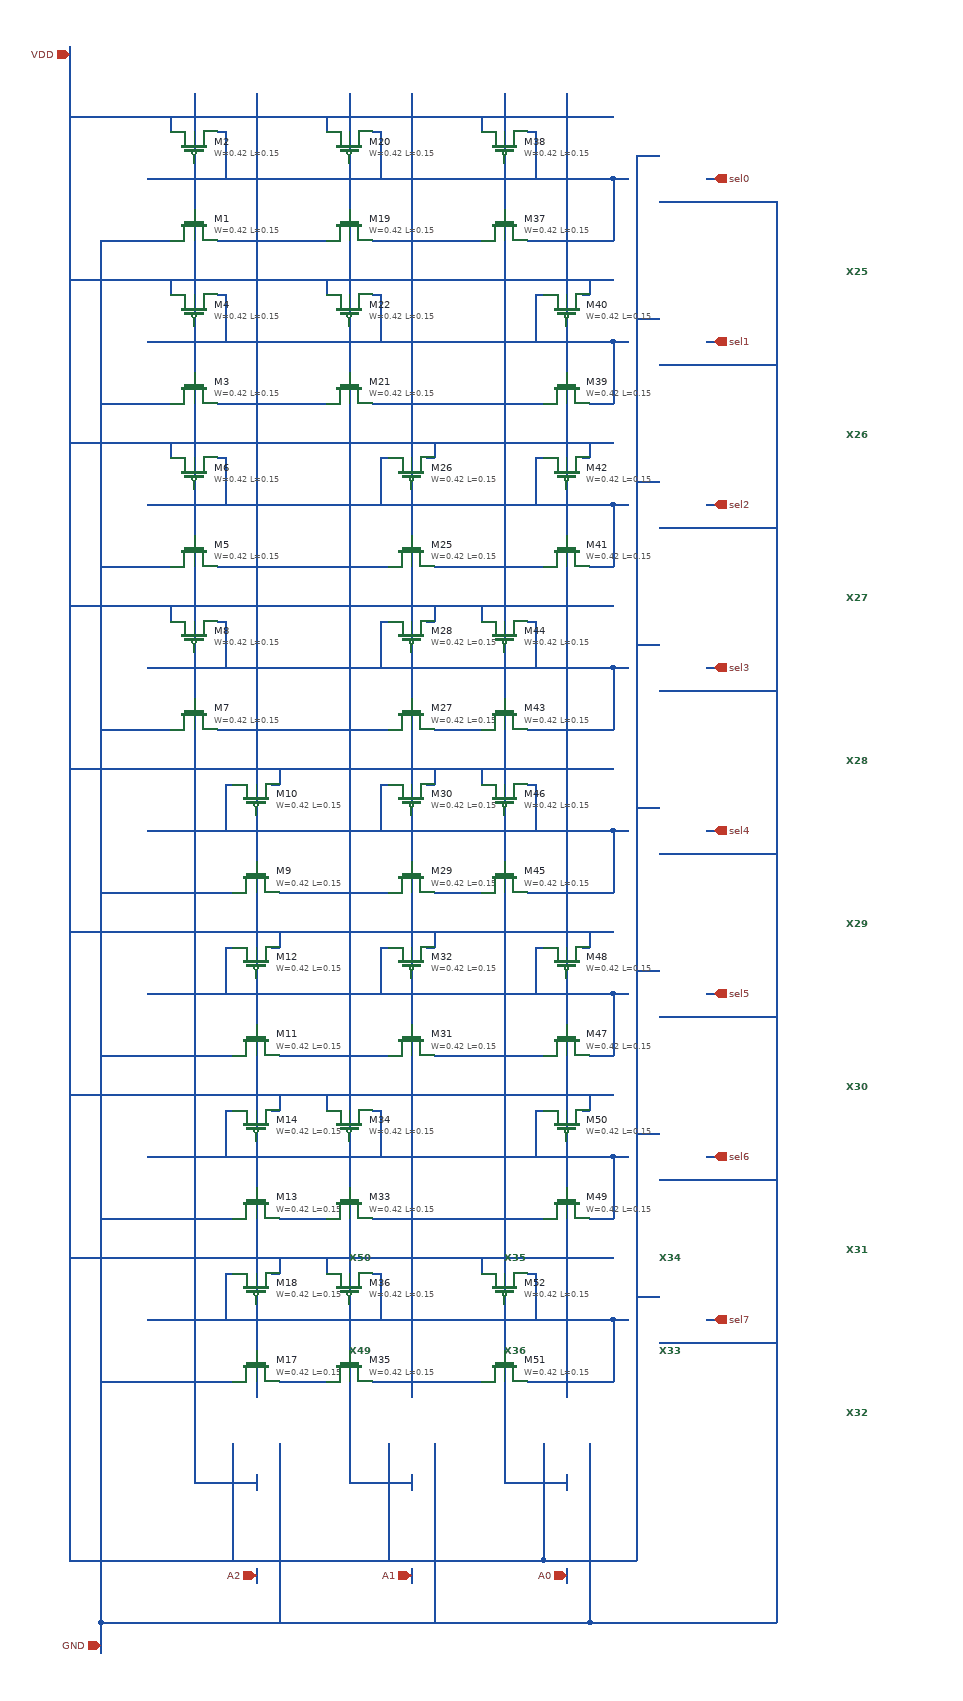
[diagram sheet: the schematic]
v {xschem version=2.9.9 file_version=1.2 }
G {}
K {}
V {}
S {}
E {}
N -1576485940 -284840100 -1576485790 -284840100 { lab=#net1}
N -1576485880 -284840160 -1576485870 -284840160 { lab=#net1}
N -1576485870 -284840160 -1576485870 -284840100 { lab=#net1}
N -1576485950 -284840100 -1576485940 -284840100 { lab=#net1}
N -1576485940 -284840180 -1576485940 -284840160 { lab=VDD}
N -1576485950 -284840020 -1576485940 -284840020 { lab=GND}
N -1576485880 -284840020 -1576485790 -284840020 { lab=#net2}
N -1576485910 -284840120 -1576485910 -284840060 { lab=#net3}
N -1576485910 -284840020 -1576485910 -284840000 { lab=#net3}
N -1576485910 -284840210 -1576485910 -284840150 { lab=#net3}
N -1576485970 -284840180 -1576485790 -284840180 { lab=VDD}
N -1576485830 -284840200 -1576485830 -284840000 { lab=#net4}
N -1576485910 -284840060 -1576485910 -284840020 { lab=#net3}
N -1576485910 -284840150 -1576485910 -284840120 { lab=#net3}
N -1576485970 -284840020 -1576485950 -284840020 { lab=GND}
N -1576485970 -284840100 -1576485950 -284840100 { lab=#net1}
N -1576485830 -284840210 -1576485830 -284840200 { lab=#net4}
N -1576485790 -284840180 -1576485770 -284840180 { lab=VDD}
N -1576485790 -284840100 -1576485770 -284840100 { lab=#net1}
N -1576485790 -284840020 -1576485770 -284840020 { lab=#net2}
N -1576485940 -284839890 -1576485790 -284839890 { lab=#net5}
N -1576485880 -284839950 -1576485870 -284839950 { lab=#net5}
N -1576485870 -284839950 -1576485870 -284839890 { lab=#net5}
N -1576485950 -284839890 -1576485940 -284839890 { lab=#net5}
N -1576485940 -284839970 -1576485940 -284839950 { lab=VDD}
N -1576485950 -284839810 -1576485940 -284839810 { lab=GND}
N -1576485880 -284839810 -1576485790 -284839810 { lab=#net6}
N -1576485910 -284839910 -1576485910 -284839850 { lab=#net3}
N -1576485910 -284839810 -1576485910 -284839790 { lab=#net3}
N -1576485910 -284840000 -1576485910 -284839940 { lab=#net3}
N -1576485970 -284839970 -1576485790 -284839970 { lab=VDD}
N -1576485830 -284839990 -1576485830 -284839790 { lab=#net4}
N -1576485910 -284839850 -1576485910 -284839810 { lab=#net3}
N -1576485910 -284839940 -1576485910 -284839910 { lab=#net3}
N -1576485970 -284839810 -1576485950 -284839810 { lab=GND}
N -1576485970 -284839890 -1576485950 -284839890 { lab=#net5}
N -1576485830 -284840000 -1576485830 -284839990 { lab=#net4}
N -1576485790 -284839970 -1576485770 -284839970 { lab=VDD}
N -1576485790 -284839890 -1576485770 -284839890 { lab=#net5}
N -1576485790 -284839810 -1576485770 -284839810 { lab=#net6}
N -1576485940 -284839680 -1576485790 -284839680 { lab=#net7}
N -1576485880 -284839740 -1576485870 -284839740 { lab=#net7}
N -1576485870 -284839740 -1576485870 -284839680 { lab=#net7}
N -1576485950 -284839680 -1576485940 -284839680 { lab=#net7}
N -1576485940 -284839760 -1576485940 -284839740 { lab=VDD}
N -1576485950 -284839600 -1576485940 -284839600 { lab=GND}
N -1576485880 -284839600 -1576485790 -284839600 { lab=#net8}
N -1576485910 -284839700 -1576485910 -284839640 { lab=#net3}
N -1576485910 -284839600 -1576485910 -284839580 { lab=#net3}
N -1576485910 -284839790 -1576485910 -284839730 { lab=#net3}
N -1576485970 -284839760 -1576485790 -284839760 { lab=VDD}
N -1576485830 -284839780 -1576485830 -284839580 { lab=#net4}
N -1576485910 -284839640 -1576485910 -284839600 { lab=#net3}
N -1576485910 -284839730 -1576485910 -284839700 { lab=#net3}
N -1576485970 -284839600 -1576485950 -284839600 { lab=GND}
N -1576485970 -284839680 -1576485950 -284839680 { lab=#net7}
N -1576485830 -284839790 -1576485830 -284839780 { lab=#net4}
N -1576485790 -284839760 -1576485770 -284839760 { lab=VDD}
N -1576485790 -284839680 -1576485770 -284839680 { lab=#net7}
N -1576485790 -284839600 -1576485770 -284839600 { lab=#net8}
N -1576485940 -284839470 -1576485790 -284839470 { lab=#net9}
N -1576485880 -284839530 -1576485870 -284839530 { lab=#net9}
N -1576485870 -284839530 -1576485870 -284839470 { lab=#net9}
N -1576485950 -284839470 -1576485940 -284839470 { lab=#net9}
N -1576485940 -284839550 -1576485940 -284839530 { lab=VDD}
N -1576485950 -284839390 -1576485940 -284839390 { lab=GND}
N -1576485880 -284839390 -1576485790 -284839390 { lab=#net10}
N -1576485910 -284839490 -1576485910 -284839430 { lab=#net3}
N -1576485910 -284839390 -1576485910 -284839370 { lab=#net3}
N -1576485910 -284839580 -1576485910 -284839520 { lab=#net3}
N -1576485970 -284839550 -1576485790 -284839550 { lab=VDD}
N -1576485830 -284839570 -1576485830 -284839370 { lab=#net4}
N -1576485910 -284839430 -1576485910 -284839390 { lab=#net3}
N -1576485910 -284839520 -1576485910 -284839490 { lab=#net3}
N -1576485970 -284839390 -1576485950 -284839390 { lab=GND}
N -1576485970 -284839470 -1576485950 -284839470 { lab=#net9}
N -1576485830 -284839580 -1576485830 -284839570 { lab=#net4}
N -1576485790 -284839550 -1576485770 -284839550 { lab=VDD}
N -1576485790 -284839470 -1576485770 -284839470 { lab=#net9}
N -1576485790 -284839390 -1576485770 -284839390 { lab=#net10}
N -1576485810 -284839320 -1576485800 -284839320 { lab=VDD}
N -1576485800 -284839340 -1576485800 -284839320 { lab=VDD}
N -1576485830 -284839280 -1576485830 -284839220 { lab=#net4}
N -1576485830 -284839180 -1576485830 -284839160 { lab=#net4}
N -1576485830 -284839370 -1576485830 -284839310 { lab=#net4}
N -1576485830 -284839220 -1576485830 -284839180 { lab=#net4}
N -1576485830 -284839310 -1576485830 -284839280 { lab=#net4}
N -1576485910 -284839370 -1576485910 -284839160 { lab=#net3}
N -1576485870 -284839320 -1576485860 -284839320 { lab=#net11}
N -1576485870 -284839320 -1576485870 -284839260 { lab=#net11}
N -1576485800 -284839180 -1576485790 -284839180 { lab=#net12}
N -1576485950 -284839180 -1576485860 -284839180 { lab=GND}
N -1576485950 -284839260 -1576485800 -284839260 { lab=#net11}
N -1576485950 -284839340 -1576485770 -284839340 { lab=VDD}
N -1576485800 -284839260 -1576485780 -284839260 { lab=#net11}
N -1576485780 -284839260 -1576485770 -284839260 { lab=#net11}
N -1576485790 -284839180 -1576485770 -284839180 { lab=#net12}
N -1576485970 -284839180 -1576485950 -284839180 { lab=GND}
N -1576485970 -284839260 -1576485950 -284839260 { lab=#net11}
N -1576485970 -284839340 -1576485950 -284839340 { lab=VDD}
N -1576485810 -284839110 -1576485800 -284839110 { lab=VDD}
N -1576485800 -284839130 -1576485800 -284839110 { lab=VDD}
N -1576485830 -284839070 -1576485830 -284839010 { lab=#net4}
N -1576485830 -284838970 -1576485830 -284838950 { lab=#net4}
N -1576485830 -284839160 -1576485830 -284839100 { lab=#net4}
N -1576485830 -284839010 -1576485830 -284838970 { lab=#net4}
N -1576485830 -284839100 -1576485830 -284839070 { lab=#net4}
N -1576485910 -284839160 -1576485910 -284838950 { lab=#net3}
N -1576485870 -284839110 -1576485860 -284839110 { lab=#net13}
N -1576485870 -284839110 -1576485870 -284839050 { lab=#net13}
N -1576485800 -284838970 -1576485790 -284838970 { lab=#net14}
N -1576485950 -284838970 -1576485860 -284838970 { lab=GND}
N -1576485950 -284839050 -1576485800 -284839050 { lab=#net13}
N -1576485950 -284839130 -1576485770 -284839130 { lab=VDD}
N -1576485800 -284839050 -1576485780 -284839050 { lab=#net13}
N -1576485780 -284839050 -1576485770 -284839050 { lab=#net13}
N -1576485790 -284838970 -1576485770 -284838970 { lab=#net14}
N -1576485970 -284838970 -1576485950 -284838970 { lab=GND}
N -1576485970 -284839050 -1576485950 -284839050 { lab=#net13}
N -1576485970 -284839130 -1576485950 -284839130 { lab=VDD}
N -1576485810 -284838900 -1576485800 -284838900 { lab=VDD}
N -1576485800 -284838920 -1576485800 -284838900 { lab=VDD}
N -1576485830 -284838860 -1576485830 -284838800 { lab=#net4}
N -1576485830 -284838760 -1576485830 -284838740 { lab=#net4}
N -1576485830 -284838950 -1576485830 -284838890 { lab=#net4}
N -1576485830 -284838800 -1576485830 -284838760 { lab=#net4}
N -1576485830 -284838890 -1576485830 -284838860 { lab=#net4}
N -1576485910 -284838950 -1576485910 -284838740 { lab=#net3}
N -1576485870 -284838900 -1576485860 -284838900 { lab=#net15}
N -1576485870 -284838900 -1576485870 -284838840 { lab=#net15}
N -1576485800 -284838760 -1576485790 -284838760 { lab=#net16}
N -1576485950 -284838760 -1576485860 -284838760 { lab=GND}
N -1576485950 -284838840 -1576485800 -284838840 { lab=#net15}
N -1576485950 -284838920 -1576485770 -284838920 { lab=VDD}
N -1576485800 -284838840 -1576485780 -284838840 { lab=#net15}
N -1576485780 -284838840 -1576485770 -284838840 { lab=#net15}
N -1576485790 -284838760 -1576485770 -284838760 { lab=#net16}
N -1576485970 -284838760 -1576485950 -284838760 { lab=GND}
N -1576485970 -284838840 -1576485950 -284838840 { lab=#net15}
N -1576485970 -284838920 -1576485950 -284838920 { lab=VDD}
N -1576485810 -284838690 -1576485800 -284838690 { lab=VDD}
N -1576485800 -284838710 -1576485800 -284838690 { lab=VDD}
N -1576485830 -284838650 -1576485830 -284838590 { lab=#net4}
N -1576485830 -284838550 -1576485830 -284838530 { lab=#net4}
N -1576485830 -284838740 -1576485830 -284838680 { lab=#net4}
N -1576485830 -284838590 -1576485830 -284838550 { lab=#net4}
N -1576485830 -284838680 -1576485830 -284838650 { lab=#net4}
N -1576485910 -284838740 -1576485910 -284838530 { lab=#net3}
N -1576485870 -284838690 -1576485860 -284838690 { lab=#net17}
N -1576485870 -284838690 -1576485870 -284838630 { lab=#net17}
N -1576485800 -284838550 -1576485790 -284838550 { lab=#net18}
N -1576485950 -284838550 -1576485860 -284838550 { lab=GND}
N -1576485950 -284838630 -1576485800 -284838630 { lab=#net17}
N -1576485950 -284838710 -1576485770 -284838710 { lab=VDD}
N -1576485800 -284838630 -1576485780 -284838630 { lab=#net17}
N -1576485780 -284838630 -1576485770 -284838630 { lab=#net17}
N -1576485790 -284838550 -1576485770 -284838550 { lab=#net18}
N -1576485970 -284838550 -1576485950 -284838550 { lab=GND}
N -1576485970 -284838630 -1576485950 -284838630 { lab=#net17}
N -1576485970 -284838710 -1576485950 -284838710 { lab=VDD}
N -1576485740 -284840100 -1576485590 -284840100 { lab=#net1}
N -1576485680 -284840160 -1576485670 -284840160 { lab=#net1}
N -1576485670 -284840160 -1576485670 -284840100 { lab=#net1}
N -1576485750 -284840100 -1576485740 -284840100 { lab=#net1}
N -1576485740 -284840180 -1576485740 -284840160 { lab=VDD}
N -1576485750 -284840020 -1576485740 -284840020 { lab=#net2}
N -1576485680 -284840020 -1576485590 -284840020 { lab=#net19}
N -1576485710 -284840120 -1576485710 -284840060 { lab=#net20}
N -1576485710 -284840020 -1576485710 -284840000 { lab=#net20}
N -1576485710 -284840210 -1576485710 -284840150 { lab=#net20}
N -1576485770 -284840180 -1576485590 -284840180 { lab=VDD}
N -1576485630 -284840200 -1576485630 -284840000 { lab=#net21}
N -1576485710 -284840060 -1576485710 -284840020 { lab=#net20}
N -1576485710 -284840150 -1576485710 -284840120 { lab=#net20}
N -1576485770 -284840020 -1576485750 -284840020 { lab=#net2}
N -1576485770 -284840100 -1576485750 -284840100 { lab=#net1}
N -1576485630 -284840210 -1576485630 -284840200 { lab=#net21}
N -1576485590 -284840180 -1576485570 -284840180 { lab=VDD}
N -1576485590 -284840100 -1576485570 -284840100 { lab=#net1}
N -1576485590 -284840020 -1576485570 -284840020 { lab=#net19}
N -1576485740 -284839890 -1576485590 -284839890 { lab=#net5}
N -1576485680 -284839950 -1576485670 -284839950 { lab=#net5}
N -1576485670 -284839950 -1576485670 -284839890 { lab=#net5}
N -1576485750 -284839890 -1576485740 -284839890 { lab=#net5}
N -1576485740 -284839970 -1576485740 -284839950 { lab=VDD}
N -1576485750 -284839810 -1576485740 -284839810 { lab=#net6}
N -1576485680 -284839810 -1576485590 -284839810 { lab=#net22}
N -1576485710 -284839910 -1576485710 -284839850 { lab=#net20}
N -1576485710 -284839810 -1576485710 -284839790 { lab=#net20}
N -1576485710 -284840000 -1576485710 -284839940 { lab=#net20}
N -1576485770 -284839970 -1576485590 -284839970 { lab=VDD}
N -1576485630 -284839990 -1576485630 -284839790 { lab=#net21}
N -1576485710 -284839850 -1576485710 -284839810 { lab=#net20}
N -1576485710 -284839940 -1576485710 -284839910 { lab=#net20}
N -1576485770 -284839810 -1576485750 -284839810 { lab=#net6}
N -1576485770 -284839890 -1576485750 -284839890 { lab=#net5}
N -1576485630 -284840000 -1576485630 -284839990 { lab=#net21}
N -1576485590 -284839970 -1576485570 -284839970 { lab=VDD}
N -1576485590 -284839890 -1576485570 -284839890 { lab=#net5}
N -1576485590 -284839810 -1576485570 -284839810 { lab=#net22}
N -1576485610 -284839740 -1576485600 -284839740 { lab=VDD}
N -1576485600 -284839760 -1576485600 -284839740 { lab=VDD}
N -1576485630 -284839700 -1576485630 -284839640 { lab=#net21}
N -1576485630 -284839600 -1576485630 -284839580 { lab=#net21}
N -1576485630 -284839790 -1576485630 -284839730 { lab=#net21}
N -1576485630 -284839640 -1576485630 -284839600 { lab=#net21}
N -1576485630 -284839730 -1576485630 -284839700 { lab=#net21}
N -1576485710 -284839790 -1576485710 -284839580 { lab=#net20}
N -1576485670 -284839740 -1576485660 -284839740 { lab=#net7}
N -1576485670 -284839740 -1576485670 -284839680 { lab=#net7}
N -1576485600 -284839600 -1576485590 -284839600 { lab=#net23}
N -1576485750 -284839600 -1576485660 -284839600 { lab=#net8}
N -1576485750 -284839680 -1576485600 -284839680 { lab=#net7}
N -1576485750 -284839760 -1576485570 -284839760 { lab=VDD}
N -1576485600 -284839680 -1576485580 -284839680 { lab=#net7}
N -1576485580 -284839680 -1576485570 -284839680 { lab=#net7}
N -1576485590 -284839600 -1576485570 -284839600 { lab=#net23}
N -1576485770 -284839600 -1576485750 -284839600 { lab=#net8}
N -1576485770 -284839680 -1576485750 -284839680 { lab=#net7}
N -1576485770 -284839760 -1576485750 -284839760 { lab=VDD}
N -1576485610 -284839530 -1576485600 -284839530 { lab=VDD}
N -1576485600 -284839550 -1576485600 -284839530 { lab=VDD}
N -1576485630 -284839490 -1576485630 -284839430 { lab=#net21}
N -1576485630 -284839390 -1576485630 -284839370 { lab=#net21}
N -1576485630 -284839580 -1576485630 -284839520 { lab=#net21}
N -1576485630 -284839430 -1576485630 -284839390 { lab=#net21}
N -1576485630 -284839520 -1576485630 -284839490 { lab=#net21}
N -1576485710 -284839580 -1576485710 -284839370 { lab=#net20}
N -1576485670 -284839530 -1576485660 -284839530 { lab=#net9}
N -1576485670 -284839530 -1576485670 -284839470 { lab=#net9}
N -1576485600 -284839390 -1576485590 -284839390 { lab=#net24}
N -1576485750 -284839390 -1576485660 -284839390 { lab=#net10}
N -1576485750 -284839470 -1576485600 -284839470 { lab=#net9}
N -1576485750 -284839550 -1576485570 -284839550 { lab=VDD}
N -1576485600 -284839470 -1576485580 -284839470 { lab=#net9}
N -1576485580 -284839470 -1576485570 -284839470 { lab=#net9}
N -1576485590 -284839390 -1576485570 -284839390 { lab=#net24}
N -1576485770 -284839390 -1576485750 -284839390 { lab=#net10}
N -1576485770 -284839470 -1576485750 -284839470 { lab=#net9}
N -1576485770 -284839550 -1576485750 -284839550 { lab=VDD}
N -1576485610 -284839320 -1576485600 -284839320 { lab=VDD}
N -1576485600 -284839340 -1576485600 -284839320 { lab=VDD}
N -1576485630 -284839280 -1576485630 -284839220 { lab=#net21}
N -1576485630 -284839180 -1576485630 -284839160 { lab=#net21}
N -1576485630 -284839370 -1576485630 -284839310 { lab=#net21}
N -1576485630 -284839220 -1576485630 -284839180 { lab=#net21}
N -1576485630 -284839310 -1576485630 -284839280 { lab=#net21}
N -1576485710 -284839370 -1576485710 -284839160 { lab=#net20}
N -1576485670 -284839320 -1576485660 -284839320 { lab=#net11}
N -1576485670 -284839320 -1576485670 -284839260 { lab=#net11}
N -1576485600 -284839180 -1576485590 -284839180 { lab=#net25}
N -1576485750 -284839180 -1576485660 -284839180 { lab=#net12}
N -1576485750 -284839260 -1576485600 -284839260 { lab=#net11}
N -1576485750 -284839340 -1576485570 -284839340 { lab=VDD}
N -1576485600 -284839260 -1576485580 -284839260 { lab=#net11}
N -1576485580 -284839260 -1576485570 -284839260 { lab=#net11}
N -1576485590 -284839180 -1576485570 -284839180 { lab=#net25}
N -1576485770 -284839180 -1576485750 -284839180 { lab=#net12}
N -1576485770 -284839260 -1576485750 -284839260 { lab=#net11}
N -1576485770 -284839340 -1576485750 -284839340 { lab=VDD}
N -1576485610 -284839110 -1576485600 -284839110 { lab=VDD}
N -1576485600 -284839130 -1576485600 -284839110 { lab=VDD}
N -1576485630 -284839070 -1576485630 -284839010 { lab=#net21}
N -1576485630 -284838970 -1576485630 -284838950 { lab=#net21}
N -1576485630 -284839160 -1576485630 -284839100 { lab=#net21}
N -1576485630 -284839010 -1576485630 -284838970 { lab=#net21}
N -1576485630 -284839100 -1576485630 -284839070 { lab=#net21}
N -1576485710 -284839160 -1576485710 -284838950 { lab=#net20}
N -1576485670 -284839110 -1576485660 -284839110 { lab=#net13}
N -1576485670 -284839110 -1576485670 -284839050 { lab=#net13}
N -1576485600 -284838970 -1576485590 -284838970 { lab=#net26}
N -1576485750 -284838970 -1576485660 -284838970 { lab=#net14}
N -1576485750 -284839050 -1576485600 -284839050 { lab=#net13}
N -1576485750 -284839130 -1576485570 -284839130 { lab=VDD}
N -1576485600 -284839050 -1576485580 -284839050 { lab=#net13}
N -1576485580 -284839050 -1576485570 -284839050 { lab=#net13}
N -1576485590 -284838970 -1576485570 -284838970 { lab=#net26}
N -1576485770 -284838970 -1576485750 -284838970 { lab=#net14}
N -1576485770 -284839050 -1576485750 -284839050 { lab=#net13}
N -1576485770 -284839130 -1576485750 -284839130 { lab=VDD}
N -1576485740 -284838840 -1576485590 -284838840 { lab=#net15}
N -1576485680 -284838900 -1576485670 -284838900 { lab=#net15}
N -1576485670 -284838900 -1576485670 -284838840 { lab=#net15}
N -1576485750 -284838840 -1576485740 -284838840 { lab=#net15}
N -1576485740 -284838920 -1576485740 -284838900 { lab=VDD}
N -1576485750 -284838760 -1576485740 -284838760 { lab=#net16}
N -1576485680 -284838760 -1576485590 -284838760 { lab=#net27}
N -1576485710 -284838860 -1576485710 -284838800 { lab=#net20}
N -1576485710 -284838760 -1576485710 -284838740 { lab=#net20}
N -1576485710 -284838950 -1576485710 -284838890 { lab=#net20}
N -1576485770 -284838920 -1576485590 -284838920 { lab=VDD}
N -1576485630 -284838940 -1576485630 -284838740 { lab=#net21}
N -1576485710 -284838800 -1576485710 -284838760 { lab=#net20}
N -1576485710 -284838890 -1576485710 -284838860 { lab=#net20}
N -1576485770 -284838760 -1576485750 -284838760 { lab=#net16}
N -1576485770 -284838840 -1576485750 -284838840 { lab=#net15}
N -1576485630 -284838950 -1576485630 -284838940 { lab=#net21}
N -1576485590 -284838920 -1576485570 -284838920 { lab=VDD}
N -1576485590 -284838840 -1576485570 -284838840 { lab=#net15}
N -1576485590 -284838760 -1576485570 -284838760 { lab=#net27}
N -1576485740 -284838630 -1576485590 -284838630 { lab=#net17}
N -1576485680 -284838690 -1576485670 -284838690 { lab=#net17}
N -1576485670 -284838690 -1576485670 -284838630 { lab=#net17}
N -1576485750 -284838630 -1576485740 -284838630 { lab=#net17}
N -1576485740 -284838710 -1576485740 -284838690 { lab=VDD}
N -1576485750 -284838550 -1576485740 -284838550 { lab=#net18}
N -1576485680 -284838550 -1576485590 -284838550 { lab=#net28}
N -1576485710 -284838650 -1576485710 -284838590 { lab=#net20}
N -1576485710 -284838550 -1576485710 -284838530 { lab=#net20}
N -1576485710 -284838740 -1576485710 -284838680 { lab=#net20}
N -1576485770 -284838710 -1576485590 -284838710 { lab=VDD}
N -1576485630 -284838730 -1576485630 -284838530 { lab=#net21}
N -1576485710 -284838590 -1576485710 -284838550 { lab=#net20}
N -1576485710 -284838680 -1576485710 -284838650 { lab=#net20}
N -1576485770 -284838550 -1576485750 -284838550 { lab=#net18}
N -1576485770 -284838630 -1576485750 -284838630 { lab=#net17}
N -1576485630 -284838740 -1576485630 -284838730 { lab=#net21}
N -1576485590 -284838710 -1576485570 -284838710 { lab=VDD}
N -1576485590 -284838630 -1576485570 -284838630 { lab=#net17}
N -1576485590 -284838550 -1576485570 -284838550 { lab=#net28}
N -1576485540 -284840100 -1576485390 -284840100 { lab=#net1}
N -1576485480 -284840160 -1576485470 -284840160 { lab=#net1}
N -1576485470 -284840160 -1576485470 -284840100 { lab=#net1}
N -1576485550 -284840100 -1576485540 -284840100 { lab=#net1}
N -1576485540 -284840180 -1576485540 -284840160 { lab=VDD}
N -1576485550 -284840020 -1576485540 -284840020 { lab=#net19}
N -1576485480 -284840020 -1576485390 -284840020 { lab=#net1}
N -1576485510 -284840120 -1576485510 -284840060 { lab=#net29}
N -1576485510 -284840020 -1576485510 -284840000 { lab=#net29}
N -1576485510 -284840210 -1576485510 -284840150 { lab=#net29}
N -1576485570 -284840180 -1576485390 -284840180 { lab=VDD}
N -1576485430 -284840200 -1576485430 -284840000 { lab=#net30}
N -1576485510 -284840060 -1576485510 -284840020 { lab=#net29}
N -1576485510 -284840150 -1576485510 -284840120 { lab=#net29}
N -1576485570 -284840020 -1576485550 -284840020 { lab=#net19}
N -1576485570 -284840100 -1576485550 -284840100 { lab=#net1}
N -1576485430 -284840210 -1576485430 -284840200 { lab=#net30}
N -1576485390 -284840180 -1576485370 -284840180 { lab=VDD}
N -1576485390 -284840100 -1576485370 -284840100 { lab=#net1}
N -1576485390 -284840020 -1576485370 -284840020 { lab=#net1}
N -1576485410 -284839950 -1576485400 -284839950 { lab=VDD}
N -1576485400 -284839970 -1576485400 -284839950 { lab=VDD}
N -1576485430 -284839910 -1576485430 -284839850 { lab=#net30}
N -1576485430 -284839810 -1576485430 -284839790 { lab=#net30}
N -1576485430 -284840000 -1576485430 -284839940 { lab=#net30}
N -1576485430 -284839850 -1576485430 -284839810 { lab=#net30}
N -1576485430 -284839940 -1576485430 -284839910 { lab=#net30}
N -1576485510 -284840000 -1576485510 -284839790 { lab=#net29}
N -1576485470 -284839950 -1576485460 -284839950 { lab=#net5}
N -1576485470 -284839950 -1576485470 -284839890 { lab=#net5}
N -1576485400 -284839810 -1576485390 -284839810 { lab=#net5}
N -1576485550 -284839810 -1576485460 -284839810 { lab=#net22}
N -1576485550 -284839890 -1576485400 -284839890 { lab=#net5}
N -1576485550 -284839970 -1576485370 -284839970 { lab=VDD}
N -1576485400 -284839890 -1576485380 -284839890 { lab=#net5}
N -1576485380 -284839890 -1576485370 -284839890 { lab=#net5}
N -1576485390 -284839810 -1576485370 -284839810 { lab=#net5}
N -1576485570 -284839810 -1576485550 -284839810 { lab=#net22}
N -1576485570 -284839890 -1576485550 -284839890 { lab=#net5}
N -1576485570 -284839970 -1576485550 -284839970 { lab=VDD}
N -1576485410 -284839740 -1576485400 -284839740 { lab=VDD}
N -1576485400 -284839760 -1576485400 -284839740 { lab=VDD}
N -1576485430 -284839700 -1576485430 -284839640 { lab=#net30}
N -1576485430 -284839600 -1576485430 -284839580 { lab=#net30}
N -1576485430 -284839790 -1576485430 -284839730 { lab=#net30}
N -1576485430 -284839640 -1576485430 -284839600 { lab=#net30}
N -1576485430 -284839730 -1576485430 -284839700 { lab=#net30}
N -1576485510 -284839790 -1576485510 -284839580 { lab=#net29}
N -1576485470 -284839740 -1576485460 -284839740 { lab=#net7}
N -1576485470 -284839740 -1576485470 -284839680 { lab=#net7}
N -1576485400 -284839600 -1576485390 -284839600 { lab=#net7}
N -1576485550 -284839600 -1576485460 -284839600 { lab=#net23}
N -1576485550 -284839680 -1576485400 -284839680 { lab=#net7}
N -1576485550 -284839760 -1576485370 -284839760 { lab=VDD}
N -1576485400 -284839680 -1576485380 -284839680 { lab=#net7}
N -1576485380 -284839680 -1576485370 -284839680 { lab=#net7}
N -1576485390 -284839600 -1576485370 -284839600 { lab=#net7}
N -1576485570 -284839600 -1576485550 -284839600 { lab=#net23}
N -1576485570 -284839680 -1576485550 -284839680 { lab=#net7}
N -1576485570 -284839760 -1576485550 -284839760 { lab=VDD}
N -1576485540 -284839470 -1576485390 -284839470 { lab=#net9}
N -1576485480 -284839530 -1576485470 -284839530 { lab=#net9}
N -1576485470 -284839530 -1576485470 -284839470 { lab=#net9}
N -1576485550 -284839470 -1576485540 -284839470 { lab=#net9}
N -1576485540 -284839550 -1576485540 -284839530 { lab=VDD}
N -1576485550 -284839390 -1576485540 -284839390 { lab=#net24}
N -1576485480 -284839390 -1576485390 -284839390 { lab=#net9}
N -1576485510 -284839490 -1576485510 -284839430 { lab=#net29}
N -1576485510 -284839390 -1576485510 -284839370 { lab=#net29}
N -1576485510 -284839580 -1576485510 -284839520 { lab=#net29}
N -1576485570 -284839550 -1576485390 -284839550 { lab=VDD}
N -1576485430 -284839570 -1576485430 -284839370 { lab=#net30}
N -1576485510 -284839430 -1576485510 -284839390 { lab=#net29}
N -1576485510 -284839520 -1576485510 -284839490 { lab=#net29}
N -1576485570 -284839390 -1576485550 -284839390 { lab=#net24}
N -1576485570 -284839470 -1576485550 -284839470 { lab=#net9}
N -1576485430 -284839580 -1576485430 -284839570 { lab=#net30}
N -1576485390 -284839550 -1576485370 -284839550 { lab=VDD}
N -1576485390 -284839470 -1576485370 -284839470 { lab=#net9}
N -1576485390 -284839390 -1576485370 -284839390 { lab=#net9}
N -1576485540 -284839260 -1576485390 -284839260 { lab=#net11}
N -1576485480 -284839320 -1576485470 -284839320 { lab=#net11}
N -1576485470 -284839320 -1576485470 -284839260 { lab=#net11}
N -1576485550 -284839260 -1576485540 -284839260 { lab=#net11}
N -1576485540 -284839340 -1576485540 -284839320 { lab=VDD}
N -1576485550 -284839180 -1576485540 -284839180 { lab=#net25}
N -1576485480 -284839180 -1576485390 -284839180 { lab=#net11}
N -1576485510 -284839280 -1576485510 -284839220 { lab=#net29}
N -1576485510 -284839180 -1576485510 -284839160 { lab=#net29}
N -1576485510 -284839370 -1576485510 -284839310 { lab=#net29}
N -1576485570 -284839340 -1576485390 -284839340 { lab=VDD}
N -1576485430 -284839360 -1576485430 -284839160 { lab=#net30}
N -1576485510 -284839220 -1576485510 -284839180 { lab=#net29}
N -1576485510 -284839310 -1576485510 -284839280 { lab=#net29}
N -1576485570 -284839180 -1576485550 -284839180 { lab=#net25}
N -1576485570 -284839260 -1576485550 -284839260 { lab=#net11}
N -1576485430 -284839370 -1576485430 -284839360 { lab=#net30}
N -1576485390 -284839340 -1576485370 -284839340 { lab=VDD}
N -1576485390 -284839260 -1576485370 -284839260 { lab=#net11}
N -1576485390 -284839180 -1576485370 -284839180 { lab=#net11}
N -1576485410 -284839110 -1576485400 -284839110 { lab=VDD}
N -1576485400 -284839130 -1576485400 -284839110 { lab=VDD}
N -1576485430 -284839070 -1576485430 -284839010 { lab=#net30}
N -1576485430 -284838970 -1576485430 -284838950 { lab=#net30}
N -1576485430 -284839160 -1576485430 -284839100 { lab=#net30}
N -1576485430 -284839010 -1576485430 -284838970 { lab=#net30}
N -1576485430 -284839100 -1576485430 -284839070 { lab=#net30}
N -1576485510 -284839160 -1576485510 -284838950 { lab=#net29}
N -1576485470 -284839110 -1576485460 -284839110 { lab=#net13}
N -1576485470 -284839110 -1576485470 -284839050 { lab=#net13}
N -1576485400 -284838970 -1576485390 -284838970 { lab=#net13}
N -1576485550 -284838970 -1576485460 -284838970 { lab=#net26}
N -1576485550 -284839050 -1576485400 -284839050 { lab=#net13}
N -1576485550 -284839130 -1576485370 -284839130 { lab=VDD}
N -1576485400 -284839050 -1576485380 -284839050 { lab=#net13}
N -1576485380 -284839050 -1576485370 -284839050 { lab=#net13}
N -1576485390 -284838970 -1576485370 -284838970 { lab=#net13}
N -1576485570 -284838970 -1576485550 -284838970 { lab=#net26}
N -1576485570 -284839050 -1576485550 -284839050 { lab=#net13}
N -1576485570 -284839130 -1576485550 -284839130 { lab=VDD}
N -1576485410 -284838900 -1576485400 -284838900 { lab=VDD}
N -1576485400 -284838920 -1576485400 -284838900 { lab=VDD}
N -1576485430 -284838860 -1576485430 -284838800 { lab=#net30}
N -1576485430 -284838760 -1576485430 -284838740 { lab=#net30}
N -1576485430 -284838950 -1576485430 -284838890 { lab=#net30}
N -1576485430 -284838800 -1576485430 -284838760 { lab=#net30}
N -1576485430 -284838890 -1576485430 -284838860 { lab=#net30}
N -1576485510 -284838950 -1576485510 -284838740 { lab=#net29}
N -1576485470 -284838900 -1576485460 -284838900 { lab=#net15}
N -1576485470 -284838900 -1576485470 -284838840 { lab=#net15}
N -1576485400 -284838760 -1576485390 -284838760 { lab=#net15}
N -1576485550 -284838760 -1576485460 -284838760 { lab=#net27}
N -1576485550 -284838840 -1576485400 -284838840 { lab=#net15}
N -1576485550 -284838920 -1576485370 -284838920 { lab=VDD}
N -1576485400 -284838840 -1576485380 -284838840 { lab=#net15}
N -1576485380 -284838840 -1576485370 -284838840 { lab=#net15}
N -1576485390 -284838760 -1576485370 -284838760 { lab=#net15}
N -1576485570 -284838760 -1576485550 -284838760 { lab=#net27}
N -1576485570 -284838840 -1576485550 -284838840 { lab=#net15}
N -1576485570 -284838920 -1576485550 -284838920 { lab=VDD}
N -1576485540 -284838630 -1576485390 -284838630 { lab=#net17}
N -1576485480 -284838690 -1576485470 -284838690 { lab=#net17}
N -1576485470 -284838690 -1576485470 -284838630 { lab=#net17}
N -1576485550 -284838630 -1576485540 -284838630 { lab=#net17}
N -1576485540 -284838710 -1576485540 -284838690 { lab=VDD}
N -1576485550 -284838550 -1576485540 -284838550 { lab=#net28}
N -1576485480 -284838550 -1576485390 -284838550 { lab=#net17}
N -1576485510 -284838650 -1576485510 -284838590 { lab=#net29}
N -1576485510 -284838550 -1576485510 -284838530 { lab=#net29}
N -1576485510 -284838740 -1576485510 -284838680 { lab=#net29}
N -1576485570 -284838710 -1576485390 -284838710 { lab=VDD}
N -1576485430 -284838730 -1576485430 -284838530 { lab=#net30}
N -1576485510 -284838590 -1576485510 -284838550 { lab=#net29}
N -1576485510 -284838680 -1576485510 -284838650 { lab=#net29}
N -1576485570 -284838550 -1576485550 -284838550 { lab=#net28}
N -1576485570 -284838630 -1576485550 -284838630 { lab=#net17}
N -1576485430 -284838740 -1576485430 -284838730 { lab=#net30}
N -1576485390 -284838710 -1576485370 -284838710 { lab=VDD}
N -1576485390 -284838630 -1576485370 -284838630 { lab=#net17}
N -1576485390 -284838550 -1576485370 -284838550 { lab=#net17}
N -1576485370 -284840100 -1576485370 -284840020 { lab=#net1}
N -1576485370 -284839890 -1576485370 -284839810 { lab=#net5}
N -1576485370 -284839680 -1576485370 -284839600 { lab=#net7}
N -1576485370 -284839470 -1576485370 -284839390 { lab=#net9}
N -1576485370 -284839260 -1576485370 -284839180 { lab=#net11}
N -1576485370 -284839050 -1576485370 -284838970 { lab=#net13}
N -1576485370 -284838840 -1576485370 -284838760 { lab=#net15}
N -1576485370 -284838630 -1576485370 -284838550 { lab=#net17}
N -1576485370 -284838630 -1576485350 -284838630 { lab=#net17}
N -1576485370 -284840100 -1576485350 -284840100 { lab=#net1}
N -1576485370 -284839890 -1576485350 -284839890 { lab=#net5}
N -1576485370 -284839680 -1576485350 -284839680 { lab=#net7}
N -1576485370 -284839470 -1576485350 -284839470 { lab=#net9}
N -1576485370 -284839260 -1576485350 -284839260 { lab=#net11}
N -1576485370 -284839050 -1576485350 -284839050 { lab=#net13}
N -1576485370 -284838840 -1576485350 -284838840 { lab=#net15}
N -1576485830 -284838430 -1576485830 -284838410 { lab=#net3}
N -1576485830 -284838310 -1576485830 -284838290 { lab=A2}
N -1576485630 -284838430 -1576485630 -284838410 { lab=#net20}
N -1576485630 -284838310 -1576485630 -284838290 { lab=A1}
N -1576485430 -284838430 -1576485430 -284838410 { lab=#net29}
N -1576485430 -284838310 -1576485430 -284838290 { lab=A0}
N -1576485800 -284838470 -1576485800 -284838240 { lab=GND}
N -1576485600 -284838470 -1576485600 -284838240 { lab=GND}
N -1576485400 -284838470 -1576485400 -284838240 { lab=GND}
N -1576485860 -284838470 -1576485860 -284838320 { lab=VDD}
N -1576485660 -284838470 -1576485660 -284838320 { lab=VDD}
N -1576485460 -284838470 -1576485460 -284838320 { lab=VDD}
N -1576485910 -284838530 -1576485910 -284838420 { lab=#net3}
N -1576485910 -284838420 -1576485830 -284838420 { lab=#net3}
N -1576485710 -284838530 -1576485710 -284838420 { lab=#net20}
N -1576485710 -284838420 -1576485630 -284838420 { lab=#net20}
N -1576485510 -284838530 -1576485510 -284838420 { lab=#net29}
N -1576485510 -284838420 -1576485430 -284838420 { lab=#net29}
N -1576486030 -284838240 -1576485400 -284838240 { lab=GND}
N -1576486030 -284838240 -1576486030 -284838200 { lab=GND}
N -1576486070 -284838320 -1576485460 -284838320 { lab=VDD}
N -1576485250 -284840100 -1576485230 -284840100 { lab=sel0}
N -1576485250 -284839890 -1576485230 -284839890 { lab=sel1}
N -1576485250 -284839680 -1576485230 -284839680 { lab=sel2}
N -1576485250 -284839470 -1576485230 -284839470 { lab=sel3}
N -1576485250 -284839260 -1576485230 -284839260 { lab=sel4}
N -1576485250 -284839050 -1576485230 -284839050 { lab=sel5}
N -1576485250 -284838840 -1576485230 -284838840 { lab=sel6}
N -1576485250 -284838630 -1576485230 -284838630 { lab=sel7}
N -1576485460 -284838320 -1576485340 -284838320 { lab=VDD}
N -1576485340 -284838680 -1576485340 -284838320 { lab=VDD}
N -1576485340 -284840130 -1576485340 -284838680 { lab=VDD}
N -1576485340 -284840130 -1576485310 -284840130 { lab=VDD}
N -1576485340 -284839920 -1576485310 -284839920 { lab=VDD}
N -1576485340 -284839710 -1576485310 -284839710 { lab=VDD}
N -1576485340 -284839500 -1576485310 -284839500 { lab=VDD}
N -1576485340 -284839290 -1576485310 -284839290 { lab=VDD}
N -1576485340 -284839080 -1576485310 -284839080 { lab=VDD}
N -1576485340 -284838870 -1576485310 -284838870 { lab=VDD}
N -1576485340 -284838660 -1576485310 -284838660 { lab=VDD}
N -1576485400 -284838240 -1576485260 -284838240 { lab=GND}
N -1576485260 -284838240 -1576485160 -284838240 { lab=GND}
N -1576485160 -284840070 -1576485160 -284838240 { lab=GND}
N -1576485310 -284840070 -1576485160 -284840070 { lab=GND}
N -1576485310 -284839860 -1576485160 -284839860 { lab=GND}
N -1576485310 -284839650 -1576485160 -284839650 { lab=GND}
N -1576485310 -284839440 -1576485160 -284839440 { lab=GND}
N -1576485310 -284839230 -1576485160 -284839230 { lab=GND}
N -1576485310 -284839020 -1576485160 -284839020 { lab=GND}
N -1576485310 -284838810 -1576485160 -284838810 { lab=GND}
N -1576485310 -284838600 -1576485160 -284838600 { lab=GND}
N -1576486070 -284840270 -1576486070 -284838340 { lab=VDD}
N -1576486070 -284840180 -1576485970 -284840180 { lab=VDD}
N -1576486070 -284839970 -1576485970 -284839970 { lab=VDD}
N -1576486070 -284839760 -1576485970 -284839760 { lab=VDD}
N -1576486070 -284839550 -1576485970 -284839550 { lab=VDD}
N -1576486070 -284839340 -1576485970 -284839340 { lab=VDD}
N -1576486070 -284839130 -1576485970 -284839130 { lab=VDD}
N -1576486070 -284838920 -1576485970 -284838920 { lab=VDD}
N -1576486070 -284838710 -1576485970 -284838710 { lab=VDD}
N -1576486070 -284838340 -1576486070 -284838320 { lab=VDD}
N -1576486030 -284840020 -1576486030 -284838240 { lab=GND}
N -1576486030 -284840020 -1576485970 -284840020 { lab=GND}
N -1576486030 -284839810 -1576485970 -284839810 { lab=GND}
N -1576486030 -284839600 -1576485970 -284839600 { lab=GND}
N -1576486030 -284839390 -1576485970 -284839390 { lab=GND}
N -1576486030 -284839180 -1576485970 -284839180 { lab=GND}
N -1576486030 -284838970 -1576485970 -284838970 { lab=GND}
N -1576486030 -284838760 -1576485970 -284838760 { lab=GND}
N -1576486030 -284838550 -1576485970 -284838550 { lab=GND}
C {sky130_fd_pr/nfet3_01v8.sym} -1576485910 -284840040 1 0 {name=M1
L=0.15
W=0.42
body=GND
nf=1
mult=1
ad="'int((nf+1)/2) * W/nf * 0.29'" 
pd="'2*int((nf+1)/2) * (W/nf + 0.29)'"
as="'int((nf+2)/2) * W/nf * 0.29'" 
ps="'2*int((nf+2)/2) * (W/nf + 0.29)'"
nrd="'0.29 / W'" nrs="'0.29 / W'"
sa=0 sb=0 sd=0
model=nfet_01v8
spiceprefix=X
}
C {sky130_fd_pr/pfet3_01v8.sym} -1576485910 -284840140 3 0 {name=M2
L=0.15
W=0.42
body=VDD
nf=1
mult=1
ad="'int((nf+1)/2) * W/nf * 0.29'" 
pd="'2*int((nf+1)/2) * (W/nf + 0.29)'"
as="'int((nf+2)/2) * W/nf * 0.29'" 
ps="'2*int((nf+2)/2) * (W/nf + 0.29)'"
nrd="'0.29 / W'" nrs="'0.29 / W'"
sa=0 sb=0 sd=0
model=pfet_01v8
spiceprefix=X
}
C {sky130_fd_pr/nfet3_01v8.sym} -1576485910 -284839830 1 0 {name=M3
L=0.15
W=0.42
body=GND
nf=1
mult=1
ad="'int((nf+1)/2) * W/nf * 0.29'" 
pd="'2*int((nf+1)/2) * (W/nf + 0.29)'"
as="'int((nf+2)/2) * W/nf * 0.29'" 
ps="'2*int((nf+2)/2) * (W/nf + 0.29)'"
nrd="'0.29 / W'" nrs="'0.29 / W'"
sa=0 sb=0 sd=0
model=nfet_01v8
spiceprefix=X
}
C {sky130_fd_pr/pfet3_01v8.sym} -1576485910 -284839930 3 0 {name=M4
L=0.15
W=0.42
body=VDD
nf=1
mult=1
ad="'int((nf+1)/2) * W/nf * 0.29'" 
pd="'2*int((nf+1)/2) * (W/nf + 0.29)'"
as="'int((nf+2)/2) * W/nf * 0.29'" 
ps="'2*int((nf+2)/2) * (W/nf + 0.29)'"
nrd="'0.29 / W'" nrs="'0.29 / W'"
sa=0 sb=0 sd=0
model=pfet_01v8
spiceprefix=X
}
C {sky130_fd_pr/nfet3_01v8.sym} -1576485910 -284839620 1 0 {name=M5
L=0.15
W=0.42
body=GND
nf=1
mult=1
ad="'int((nf+1)/2) * W/nf * 0.29'" 
pd="'2*int((nf+1)/2) * (W/nf + 0.29)'"
as="'int((nf+2)/2) * W/nf * 0.29'" 
ps="'2*int((nf+2)/2) * (W/nf + 0.29)'"
nrd="'0.29 / W'" nrs="'0.29 / W'"
sa=0 sb=0 sd=0
model=nfet_01v8
spiceprefix=X
}
C {sky130_fd_pr/pfet3_01v8.sym} -1576485910 -284839720 3 0 {name=M6
L=0.15
W=0.42
body=VDD
nf=1
mult=1
ad="'int((nf+1)/2) * W/nf * 0.29'" 
pd="'2*int((nf+1)/2) * (W/nf + 0.29)'"
as="'int((nf+2)/2) * W/nf * 0.29'" 
ps="'2*int((nf+2)/2) * (W/nf + 0.29)'"
nrd="'0.29 / W'" nrs="'0.29 / W'"
sa=0 sb=0 sd=0
model=pfet_01v8
spiceprefix=X
}
C {sky130_fd_pr/nfet3_01v8.sym} -1576485910 -284839410 1 0 {name=M7
L=0.15
W=0.42
body=GND
nf=1
mult=1
ad="'int((nf+1)/2) * W/nf * 0.29'" 
pd="'2*int((nf+1)/2) * (W/nf + 0.29)'"
as="'int((nf+2)/2) * W/nf * 0.29'" 
ps="'2*int((nf+2)/2) * (W/nf + 0.29)'"
nrd="'0.29 / W'" nrs="'0.29 / W'"
sa=0 sb=0 sd=0
model=nfet_01v8
spiceprefix=X
}
C {sky130_fd_pr/pfet3_01v8.sym} -1576485910 -284839510 3 0 {name=M8
L=0.15
W=0.42
body=VDD
nf=1
mult=1
ad="'int((nf+1)/2) * W/nf * 0.29'" 
pd="'2*int((nf+1)/2) * (W/nf + 0.29)'"
as="'int((nf+2)/2) * W/nf * 0.29'" 
ps="'2*int((nf+2)/2) * (W/nf + 0.29)'"
nrd="'0.29 / W'" nrs="'0.29 / W'"
sa=0 sb=0 sd=0
model=pfet_01v8
spiceprefix=X
}
C {sky130_fd_pr/nfet3_01v8.sym} -1576485830 -284839200 3 1 {name=M9
L=0.15
W=0.42
body=GND
nf=1
mult=1
ad="'int((nf+1)/2) * W/nf * 0.29'" 
pd="'2*int((nf+1)/2) * (W/nf + 0.29)'"
as="'int((nf+2)/2) * W/nf * 0.29'" 
ps="'2*int((nf+2)/2) * (W/nf + 0.29)'"
nrd="'0.29 / W'" nrs="'0.29 / W'"
sa=0 sb=0 sd=0
model=nfet_01v8
spiceprefix=X
}
C {sky130_fd_pr/pfet3_01v8.sym} -1576485830 -284839300 1 1 {name=M10
L=0.15
W=0.42
body=VDD
nf=1
mult=1
ad="'int((nf+1)/2) * W/nf * 0.29'" 
pd="'2*int((nf+1)/2) * (W/nf + 0.29)'"
as="'int((nf+2)/2) * W/nf * 0.29'" 
ps="'2*int((nf+2)/2) * (W/nf + 0.29)'"
nrd="'0.29 / W'" nrs="'0.29 / W'"
sa=0 sb=0 sd=0
model=pfet_01v8
spiceprefix=X
}
C {sky130_fd_pr/nfet3_01v8.sym} -1576485830 -284838990 3 1 {name=M11
L=0.15
W=0.42
body=GND
nf=1
mult=1
ad="'int((nf+1)/2) * W/nf * 0.29'" 
pd="'2*int((nf+1)/2) * (W/nf + 0.29)'"
as="'int((nf+2)/2) * W/nf * 0.29'" 
ps="'2*int((nf+2)/2) * (W/nf + 0.29)'"
nrd="'0.29 / W'" nrs="'0.29 / W'"
sa=0 sb=0 sd=0
model=nfet_01v8
spiceprefix=X
}
C {sky130_fd_pr/pfet3_01v8.sym} -1576485830 -284839090 1 1 {name=M12
L=0.15
W=0.42
body=VDD
nf=1
mult=1
ad="'int((nf+1)/2) * W/nf * 0.29'" 
pd="'2*int((nf+1)/2) * (W/nf + 0.29)'"
as="'int((nf+2)/2) * W/nf * 0.29'" 
ps="'2*int((nf+2)/2) * (W/nf + 0.29)'"
nrd="'0.29 / W'" nrs="'0.29 / W'"
sa=0 sb=0 sd=0
model=pfet_01v8
spiceprefix=X
}
C {sky130_fd_pr/nfet3_01v8.sym} -1576485830 -284838780 3 1 {name=M13
L=0.15
W=0.42
body=GND
nf=1
mult=1
ad="'int((nf+1)/2) * W/nf * 0.29'" 
pd="'2*int((nf+1)/2) * (W/nf + 0.29)'"
as="'int((nf+2)/2) * W/nf * 0.29'" 
ps="'2*int((nf+2)/2) * (W/nf + 0.29)'"
nrd="'0.29 / W'" nrs="'0.29 / W'"
sa=0 sb=0 sd=0
model=nfet_01v8
spiceprefix=X
}
C {sky130_fd_pr/pfet3_01v8.sym} -1576485830 -284838880 1 1 {name=M14
L=0.15
W=0.42
body=VDD
nf=1
mult=1
ad="'int((nf+1)/2) * W/nf * 0.29'" 
pd="'2*int((nf+1)/2) * (W/nf + 0.29)'"
as="'int((nf+2)/2) * W/nf * 0.29'" 
ps="'2*int((nf+2)/2) * (W/nf + 0.29)'"
nrd="'0.29 / W'" nrs="'0.29 / W'"
sa=0 sb=0 sd=0
model=pfet_01v8
spiceprefix=X
}
C {sky130_fd_pr/nfet3_01v8.sym} -1576485830 -284838570 3 1 {name=M17
L=0.15
W=0.42
body=GND
nf=1
mult=1
ad="'int((nf+1)/2) * W/nf * 0.29'" 
pd="'2*int((nf+1)/2) * (W/nf + 0.29)'"
as="'int((nf+2)/2) * W/nf * 0.29'" 
ps="'2*int((nf+2)/2) * (W/nf + 0.29)'"
nrd="'0.29 / W'" nrs="'0.29 / W'"
sa=0 sb=0 sd=0
model=nfet_01v8
spiceprefix=X
}
C {sky130_fd_pr/pfet3_01v8.sym} -1576485830 -284838670 1 1 {name=M18
L=0.15
W=0.42
body=VDD
nf=1
mult=1
ad="'int((nf+1)/2) * W/nf * 0.29'" 
pd="'2*int((nf+1)/2) * (W/nf + 0.29)'"
as="'int((nf+2)/2) * W/nf * 0.29'" 
ps="'2*int((nf+2)/2) * (W/nf + 0.29)'"
nrd="'0.29 / W'" nrs="'0.29 / W'"
sa=0 sb=0 sd=0
model=pfet_01v8
spiceprefix=X
}
C {sky130_fd_pr/nfet3_01v8.sym} -1576485710 -284840040 1 0 {name=M19
L=0.15
W=0.42
body=GND
nf=1
mult=1
ad="'int((nf+1)/2) * W/nf * 0.29'" 
pd="'2*int((nf+1)/2) * (W/nf + 0.29)'"
as="'int((nf+2)/2) * W/nf * 0.29'" 
ps="'2*int((nf+2)/2) * (W/nf + 0.29)'"
nrd="'0.29 / W'" nrs="'0.29 / W'"
sa=0 sb=0 sd=0
model=nfet_01v8
spiceprefix=X
}
C {sky130_fd_pr/pfet3_01v8.sym} -1576485710 -284840140 3 0 {name=M20
L=0.15
W=0.42
body=VDD
nf=1
mult=1
ad="'int((nf+1)/2) * W/nf * 0.29'" 
pd="'2*int((nf+1)/2) * (W/nf + 0.29)'"
as="'int((nf+2)/2) * W/nf * 0.29'" 
ps="'2*int((nf+2)/2) * (W/nf + 0.29)'"
nrd="'0.29 / W'" nrs="'0.29 / W'"
sa=0 sb=0 sd=0
model=pfet_01v8
spiceprefix=X
}
C {sky130_fd_pr/nfet3_01v8.sym} -1576485710 -284839830 1 0 {name=M21
L=0.15
W=0.42
body=GND
nf=1
mult=1
ad="'int((nf+1)/2) * W/nf * 0.29'" 
pd="'2*int((nf+1)/2) * (W/nf + 0.29)'"
as="'int((nf+2)/2) * W/nf * 0.29'" 
ps="'2*int((nf+2)/2) * (W/nf + 0.29)'"
nrd="'0.29 / W'" nrs="'0.29 / W'"
sa=0 sb=0 sd=0
model=nfet_01v8
spiceprefix=X
}
C {sky130_fd_pr/pfet3_01v8.sym} -1576485710 -284839930 3 0 {name=M22
L=0.15
W=0.42
body=VDD
nf=1
mult=1
ad="'int((nf+1)/2) * W/nf * 0.29'" 
pd="'2*int((nf+1)/2) * (W/nf + 0.29)'"
as="'int((nf+2)/2) * W/nf * 0.29'" 
ps="'2*int((nf+2)/2) * (W/nf + 0.29)'"
nrd="'0.29 / W'" nrs="'0.29 / W'"
sa=0 sb=0 sd=0
model=pfet_01v8
spiceprefix=X
}
C {sky130_fd_pr/nfet3_01v8.sym} -1576485630 -284839620 3 1 {name=M25
L=0.15
W=0.42
body=GND
nf=1
mult=1
ad="'int((nf+1)/2) * W/nf * 0.29'" 
pd="'2*int((nf+1)/2) * (W/nf + 0.29)'"
as="'int((nf+2)/2) * W/nf * 0.29'" 
ps="'2*int((nf+2)/2) * (W/nf + 0.29)'"
nrd="'0.29 / W'" nrs="'0.29 / W'"
sa=0 sb=0 sd=0
model=nfet_01v8
spiceprefix=X
}
C {sky130_fd_pr/pfet3_01v8.sym} -1576485630 -284839720 1 1 {name=M26
L=0.15
W=0.42
body=VDD
nf=1
mult=1
ad="'int((nf+1)/2) * W/nf * 0.29'" 
pd="'2*int((nf+1)/2) * (W/nf + 0.29)'"
as="'int((nf+2)/2) * W/nf * 0.29'" 
ps="'2*int((nf+2)/2) * (W/nf + 0.29)'"
nrd="'0.29 / W'" nrs="'0.29 / W'"
sa=0 sb=0 sd=0
model=pfet_01v8
spiceprefix=X
}
C {sky130_fd_pr/nfet3_01v8.sym} -1576485630 -284839410 3 1 {name=M27
L=0.15
W=0.42
body=GND
nf=1
mult=1
ad="'int((nf+1)/2) * W/nf * 0.29'" 
pd="'2*int((nf+1)/2) * (W/nf + 0.29)'"
as="'int((nf+2)/2) * W/nf * 0.29'" 
ps="'2*int((nf+2)/2) * (W/nf + 0.29)'"
nrd="'0.29 / W'" nrs="'0.29 / W'"
sa=0 sb=0 sd=0
model=nfet_01v8
spiceprefix=X
}
C {sky130_fd_pr/pfet3_01v8.sym} -1576485630 -284839510 1 1 {name=M28
L=0.15
W=0.42
body=VDD
nf=1
mult=1
ad="'int((nf+1)/2) * W/nf * 0.29'" 
pd="'2*int((nf+1)/2) * (W/nf + 0.29)'"
as="'int((nf+2)/2) * W/nf * 0.29'" 
ps="'2*int((nf+2)/2) * (W/nf + 0.29)'"
nrd="'0.29 / W'" nrs="'0.29 / W'"
sa=0 sb=0 sd=0
model=pfet_01v8
spiceprefix=X
}
C {sky130_fd_pr/nfet3_01v8.sym} -1576485630 -284839200 3 1 {name=M29
L=0.15
W=0.42
body=GND
nf=1
mult=1
ad="'int((nf+1)/2) * W/nf * 0.29'" 
pd="'2*int((nf+1)/2) * (W/nf + 0.29)'"
as="'int((nf+2)/2) * W/nf * 0.29'" 
ps="'2*int((nf+2)/2) * (W/nf + 0.29)'"
nrd="'0.29 / W'" nrs="'0.29 / W'"
sa=0 sb=0 sd=0
model=nfet_01v8
spiceprefix=X
}
C {sky130_fd_pr/pfet3_01v8.sym} -1576485630 -284839300 1 1 {name=M30
L=0.15
W=0.42
body=VDD
nf=1
mult=1
ad="'int((nf+1)/2) * W/nf * 0.29'" 
pd="'2*int((nf+1)/2) * (W/nf + 0.29)'"
as="'int((nf+2)/2) * W/nf * 0.29'" 
ps="'2*int((nf+2)/2) * (W/nf + 0.29)'"
nrd="'0.29 / W'" nrs="'0.29 / W'"
sa=0 sb=0 sd=0
model=pfet_01v8
spiceprefix=X
}
C {sky130_fd_pr/nfet3_01v8.sym} -1576485630 -284838990 3 1 {name=M31
L=0.15
W=0.42
body=GND
nf=1
mult=1
ad="'int((nf+1)/2) * W/nf * 0.29'" 
pd="'2*int((nf+1)/2) * (W/nf + 0.29)'"
as="'int((nf+2)/2) * W/nf * 0.29'" 
ps="'2*int((nf+2)/2) * (W/nf + 0.29)'"
nrd="'0.29 / W'" nrs="'0.29 / W'"
sa=0 sb=0 sd=0
model=nfet_01v8
spiceprefix=X
}
C {sky130_fd_pr/pfet3_01v8.sym} -1576485630 -284839090 1 1 {name=M32
L=0.15
W=0.42
body=VDD
nf=1
mult=1
ad="'int((nf+1)/2) * W/nf * 0.29'" 
pd="'2*int((nf+1)/2) * (W/nf + 0.29)'"
as="'int((nf+2)/2) * W/nf * 0.29'" 
ps="'2*int((nf+2)/2) * (W/nf + 0.29)'"
nrd="'0.29 / W'" nrs="'0.29 / W'"
sa=0 sb=0 sd=0
model=pfet_01v8
spiceprefix=X
}
C {sky130_fd_pr/nfet3_01v8.sym} -1576485710 -284838780 1 0 {name=M33
L=0.15
W=0.42
body=GND
nf=1
mult=1
ad="'int((nf+1)/2) * W/nf * 0.29'" 
pd="'2*int((nf+1)/2) * (W/nf + 0.29)'"
as="'int((nf+2)/2) * W/nf * 0.29'" 
ps="'2*int((nf+2)/2) * (W/nf + 0.29)'"
nrd="'0.29 / W'" nrs="'0.29 / W'"
sa=0 sb=0 sd=0
model=nfet_01v8
spiceprefix=X
}
C {sky130_fd_pr/pfet3_01v8.sym} -1576485710 -284838880 3 0 {name=M34
L=0.15
W=0.42
body=VDD
nf=1
mult=1
ad="'int((nf+1)/2) * W/nf * 0.29'" 
pd="'2*int((nf+1)/2) * (W/nf + 0.29)'"
as="'int((nf+2)/2) * W/nf * 0.29'" 
ps="'2*int((nf+2)/2) * (W/nf + 0.29)'"
nrd="'0.29 / W'" nrs="'0.29 / W'"
sa=0 sb=0 sd=0
model=pfet_01v8
spiceprefix=X
}
C {sky130_fd_pr/nfet3_01v8.sym} -1576485710 -284838570 1 0 {name=M35
L=0.15
W=0.42
body=GND
nf=1
mult=1
ad="'int((nf+1)/2) * W/nf * 0.29'" 
pd="'2*int((nf+1)/2) * (W/nf + 0.29)'"
as="'int((nf+2)/2) * W/nf * 0.29'" 
ps="'2*int((nf+2)/2) * (W/nf + 0.29)'"
nrd="'0.29 / W'" nrs="'0.29 / W'"
sa=0 sb=0 sd=0
model=nfet_01v8
spiceprefix=X
}
C {sky130_fd_pr/pfet3_01v8.sym} -1576485710 -284838670 3 0 {name=M36
L=0.15
W=0.42
body=VDD
nf=1
mult=1
ad="'int((nf+1)/2) * W/nf * 0.29'" 
pd="'2*int((nf+1)/2) * (W/nf + 0.29)'"
as="'int((nf+2)/2) * W/nf * 0.29'" 
ps="'2*int((nf+2)/2) * (W/nf + 0.29)'"
nrd="'0.29 / W'" nrs="'0.29 / W'"
sa=0 sb=0 sd=0
model=pfet_01v8
spiceprefix=X
}
C {sky130_fd_pr/nfet3_01v8.sym} -1576485510 -284840040 1 0 {name=M37
L=0.15
W=0.42
body=GND
nf=1
mult=1
ad="'int((nf+1)/2) * W/nf * 0.29'" 
pd="'2*int((nf+1)/2) * (W/nf + 0.29)'"
as="'int((nf+2)/2) * W/nf * 0.29'" 
ps="'2*int((nf+2)/2) * (W/nf + 0.29)'"
nrd="'0.29 / W'" nrs="'0.29 / W'"
sa=0 sb=0 sd=0
model=nfet_01v8
spiceprefix=X
}
C {sky130_fd_pr/pfet3_01v8.sym} -1576485510 -284840140 3 0 {name=M38
L=0.15
W=0.42
body=VDD
nf=1
mult=1
ad="'int((nf+1)/2) * W/nf * 0.29'" 
pd="'2*int((nf+1)/2) * (W/nf + 0.29)'"
as="'int((nf+2)/2) * W/nf * 0.29'" 
ps="'2*int((nf+2)/2) * (W/nf + 0.29)'"
nrd="'0.29 / W'" nrs="'0.29 / W'"
sa=0 sb=0 sd=0
model=pfet_01v8
spiceprefix=X
}
C {sky130_fd_pr/nfet3_01v8.sym} -1576485430 -284839830 3 1 {name=M39
L=0.15
W=0.42
body=GND
nf=1
mult=1
ad="'int((nf+1)/2) * W/nf * 0.29'" 
pd="'2*int((nf+1)/2) * (W/nf + 0.29)'"
as="'int((nf+2)/2) * W/nf * 0.29'" 
ps="'2*int((nf+2)/2) * (W/nf + 0.29)'"
nrd="'0.29 / W'" nrs="'0.29 / W'"
sa=0 sb=0 sd=0
model=nfet_01v8
spiceprefix=X
}
C {sky130_fd_pr/pfet3_01v8.sym} -1576485430 -284839930 1 1 {name=M40
L=0.15
W=0.42
body=VDD
nf=1
mult=1
ad="'int((nf+1)/2) * W/nf * 0.29'" 
pd="'2*int((nf+1)/2) * (W/nf + 0.29)'"
as="'int((nf+2)/2) * W/nf * 0.29'" 
ps="'2*int((nf+2)/2) * (W/nf + 0.29)'"
nrd="'0.29 / W'" nrs="'0.29 / W'"
sa=0 sb=0 sd=0
model=pfet_01v8
spiceprefix=X
}
C {sky130_fd_pr/nfet3_01v8.sym} -1576485430 -284839620 3 1 {name=M41
L=0.15
W=0.42
body=GND
nf=1
mult=1
ad="'int((nf+1)/2) * W/nf * 0.29'" 
pd="'2*int((nf+1)/2) * (W/nf + 0.29)'"
as="'int((nf+2)/2) * W/nf * 0.29'" 
ps="'2*int((nf+2)/2) * (W/nf + 0.29)'"
nrd="'0.29 / W'" nrs="'0.29 / W'"
sa=0 sb=0 sd=0
model=nfet_01v8
spiceprefix=X
}
C {sky130_fd_pr/pfet3_01v8.sym} -1576485430 -284839720 1 1 {name=M42
L=0.15
W=0.42
body=VDD
nf=1
mult=1
ad="'int((nf+1)/2) * W/nf * 0.29'" 
pd="'2*int((nf+1)/2) * (W/nf + 0.29)'"
as="'int((nf+2)/2) * W/nf * 0.29'" 
ps="'2*int((nf+2)/2) * (W/nf + 0.29)'"
nrd="'0.29 / W'" nrs="'0.29 / W'"
sa=0 sb=0 sd=0
model=pfet_01v8
spiceprefix=X
}
C {sky130_fd_pr/nfet3_01v8.sym} -1576485510 -284839410 1 0 {name=M43
L=0.15
W=0.42
body=GND
nf=1
mult=1
ad="'int((nf+1)/2) * W/nf * 0.29'" 
pd="'2*int((nf+1)/2) * (W/nf + 0.29)'"
as="'int((nf+2)/2) * W/nf * 0.29'" 
ps="'2*int((nf+2)/2) * (W/nf + 0.29)'"
nrd="'0.29 / W'" nrs="'0.29 / W'"
sa=0 sb=0 sd=0
model=nfet_01v8
spiceprefix=X
}
C {sky130_fd_pr/pfet3_01v8.sym} -1576485510 -284839510 3 0 {name=M44
L=0.15
W=0.42
body=VDD
nf=1
mult=1
ad="'int((nf+1)/2) * W/nf * 0.29'" 
pd="'2*int((nf+1)/2) * (W/nf + 0.29)'"
as="'int((nf+2)/2) * W/nf * 0.29'" 
ps="'2*int((nf+2)/2) * (W/nf + 0.29)'"
nrd="'0.29 / W'" nrs="'0.29 / W'"
sa=0 sb=0 sd=0
model=pfet_01v8
spiceprefix=X
}
C {sky130_fd_pr/nfet3_01v8.sym} -1576485510 -284839200 1 0 {name=M45
L=0.15
W=0.42
body=GND
nf=1
mult=1
ad="'int((nf+1)/2) * W/nf * 0.29'" 
pd="'2*int((nf+1)/2) * (W/nf + 0.29)'"
as="'int((nf+2)/2) * W/nf * 0.29'" 
ps="'2*int((nf+2)/2) * (W/nf + 0.29)'"
nrd="'0.29 / W'" nrs="'0.29 / W'"
sa=0 sb=0 sd=0
model=nfet_01v8
spiceprefix=X
}
C {sky130_fd_pr/pfet3_01v8.sym} -1576485510 -284839300 3 0 {name=M46
L=0.15
W=0.42
body=VDD
nf=1
mult=1
ad="'int((nf+1)/2) * W/nf * 0.29'" 
pd="'2*int((nf+1)/2) * (W/nf + 0.29)'"
as="'int((nf+2)/2) * W/nf * 0.29'" 
ps="'2*int((nf+2)/2) * (W/nf + 0.29)'"
nrd="'0.29 / W'" nrs="'0.29 / W'"
sa=0 sb=0 sd=0
model=pfet_01v8
spiceprefix=X
}
C {sky130_fd_pr/nfet3_01v8.sym} -1576485430 -284838990 3 1 {name=M47
L=0.15
W=0.42
body=GND
nf=1
mult=1
ad="'int((nf+1)/2) * W/nf * 0.29'" 
pd="'2*int((nf+1)/2) * (W/nf + 0.29)'"
as="'int((nf+2)/2) * W/nf * 0.29'" 
ps="'2*int((nf+2)/2) * (W/nf + 0.29)'"
nrd="'0.29 / W'" nrs="'0.29 / W'"
sa=0 sb=0 sd=0
model=nfet_01v8
spiceprefix=X
}
C {sky130_fd_pr/pfet3_01v8.sym} -1576485430 -284839090 1 1 {name=M48
L=0.15
W=0.42
body=VDD
nf=1
mult=1
ad="'int((nf+1)/2) * W/nf * 0.29'" 
pd="'2*int((nf+1)/2) * (W/nf + 0.29)'"
as="'int((nf+2)/2) * W/nf * 0.29'" 
ps="'2*int((nf+2)/2) * (W/nf + 0.29)'"
nrd="'0.29 / W'" nrs="'0.29 / W'"
sa=0 sb=0 sd=0
model=pfet_01v8
spiceprefix=X
}
C {sky130_fd_pr/nfet3_01v8.sym} -1576485430 -284838780 3 1 {name=M49
L=0.15
W=0.42
body=GND
nf=1
mult=1
ad="'int((nf+1)/2) * W/nf * 0.29'" 
pd="'2*int((nf+1)/2) * (W/nf + 0.29)'"
as="'int((nf+2)/2) * W/nf * 0.29'" 
ps="'2*int((nf+2)/2) * (W/nf + 0.29)'"
nrd="'0.29 / W'" nrs="'0.29 / W'"
sa=0 sb=0 sd=0
model=nfet_01v8
spiceprefix=X
}
C {sky130_fd_pr/pfet3_01v8.sym} -1576485430 -284838880 1 1 {name=M50
L=0.15
W=0.42
body=VDD
nf=1
mult=1
ad="'int((nf+1)/2) * W/nf * 0.29'" 
pd="'2*int((nf+1)/2) * (W/nf + 0.29)'"
as="'int((nf+2)/2) * W/nf * 0.29'" 
ps="'2*int((nf+2)/2) * (W/nf + 0.29)'"
nrd="'0.29 / W'" nrs="'0.29 / W'"
sa=0 sb=0 sd=0
model=pfet_01v8
spiceprefix=X
}
C {sky130_fd_pr/nfet3_01v8.sym} -1576485510 -284838570 1 0 {name=M51
L=0.15
W=0.42
body=GND
nf=1
mult=1
ad="'int((nf+1)/2) * W/nf * 0.29'" 
pd="'2*int((nf+1)/2) * (W/nf + 0.29)'"
as="'int((nf+2)/2) * W/nf * 0.29'" 
ps="'2*int((nf+2)/2) * (W/nf + 0.29)'"
nrd="'0.29 / W'" nrs="'0.29 / W'"
sa=0 sb=0 sd=0
model=nfet_01v8
spiceprefix=X
}
C {sky130_fd_pr/pfet3_01v8.sym} -1576485510 -284838670 3 0 {name=M52
L=0.15
W=0.42
body=VDD
nf=1
mult=1
ad="'int((nf+1)/2) * W/nf * 0.29'" 
pd="'2*int((nf+1)/2) * (W/nf + 0.29)'"
as="'int((nf+2)/2) * W/nf * 0.29'" 
ps="'2*int((nf+2)/2) * (W/nf + 0.29)'"
nrd="'0.29 / W'" nrs="'0.29 / W'"
sa=0 sb=0 sd=0
model=pfet_01v8
spiceprefix=X
}
C {inv/inv_sparse_decoder.sym} -1576485070 -284839980 0 0 {name=X25 Wpmos=0.42 Lpmos=0.15 Wnmos=0.42 Lnmos=0.15}
C {inv/inv_sparse_decoder.sym} -1576485070 -284839770 0 0 {name=X26 Wpmos=0.42 Lpmos=0.15 Wnmos=0.42 Lnmos=0.15}
C {inv/inv_sparse_decoder.sym} -1576485070 -284839560 0 0 {name=X27 Wpmos=0.42 Lpmos=0.15 Wnmos=0.42 Lnmos=0.15}
C {inv/inv_sparse_decoder.sym} -1576485070 -284839350 0 0 {name=X28 Wpmos=0.42 Lpmos=0.15 Wnmos=0.42 Lnmos=0.15}
C {inv/inv_sparse_decoder.sym} -1576485070 -284839140 0 0 {name=X29 Wpmos=0.42 Lpmos=0.15 Wnmos=0.42 Lnmos=0.15}
C {inv/inv_sparse_decoder.sym} -1576485070 -284838930 0 0 {name=X30 Wpmos=0.42 Lpmos=0.15 Wnmos=0.42 Lnmos=0.15}
C {inv/inv_sparse_decoder.sym} -1576485070 -284838720 0 0 {name=X31 Wpmos=0.42 Lpmos=0.15 Wnmos=0.42 Lnmos=0.15}
C {inv/inv_sparse_decoder.sym} -1576485070 -284838510 0 0 {name=X32 Wpmos=0.42 Lpmos=0.15 Wnmos=0.42 Lnmos=0.15}
C {devices/ipin.sym} -1576485830 -284838300 3 0 {name=p9 lab=A2}
C {devices/ipin.sym} -1576485630 -284838300 3 0 {name=p10 lab=A1}
C {devices/ipin.sym} -1576485430 -284838300 3 0 {name=p11 lab=A0}
C {inv/inv_sparse_decoder.sym} -1576485310 -284838590 3 0 {name=X33 Wpmos=0.42 Lpmos=0.15 Wnmos=0.42 Lnmos=0.15}
C {inv/inv_sparse_decoder.sym} -1576485310 -284838710 3 0 {name=X34 Wpmos=0.42 Lpmos=0.15 Wnmos=0.42 Lnmos=0.15}
C {inv/inv_sparse_decoder.sym} -1576485510 -284838710 3 0 {name=X35 Wpmos=0.42 Lpmos=0.15 Wnmos=0.42 Lnmos=0.15}
C {inv/inv_sparse_decoder.sym} -1576485510 -284838590 3 0 {name=X36 Wpmos=0.42 Lpmos=0.15 Wnmos=0.42 Lnmos=0.15}
C {inv/inv_sparse_decoder.sym} -1576485710 -284838590 3 0 {name=X49 Wpmos=0.42 Lpmos=0.15 Wnmos=0.42 Lnmos=0.15}
C {inv/inv_sparse_decoder.sym} -1576485710 -284838710 3 0 {name=X50 Wpmos=0.42 Lpmos=0.15 Wnmos=0.42 Lnmos=0.15}
C {devices/opin.sym} -1576485240 -284840100 0 0 {name=p5 lab=sel0}
C {devices/opin.sym} -1576485240 -284839890 0 0 {name=p12 lab=sel1}
C {devices/opin.sym} -1576485240 -284839680 0 0 {name=p13 lab=sel2}
C {devices/opin.sym} -1576485240 -284839470 0 0 {name=p14 lab=sel3}
C {devices/opin.sym} -1576485240 -284839260 0 0 {name=p15 lab=sel4}
C {devices/opin.sym} -1576485240 -284839050 0 0 {name=p16 lab=sel5}
C {devices/opin.sym} -1576485240 -284838840 0 0 {name=p17 lab=sel6}
C {devices/opin.sym} -1576485240 -284838630 0 0 {name=p18 lab=sel7}
C {devices/iopin.sym} -1576486070 -284840260 3 0 {name=p19 lab=VDD}
C {devices/iopin.sym} -1576486030 -284838210 1 0 {name=p20 lab=GND}
